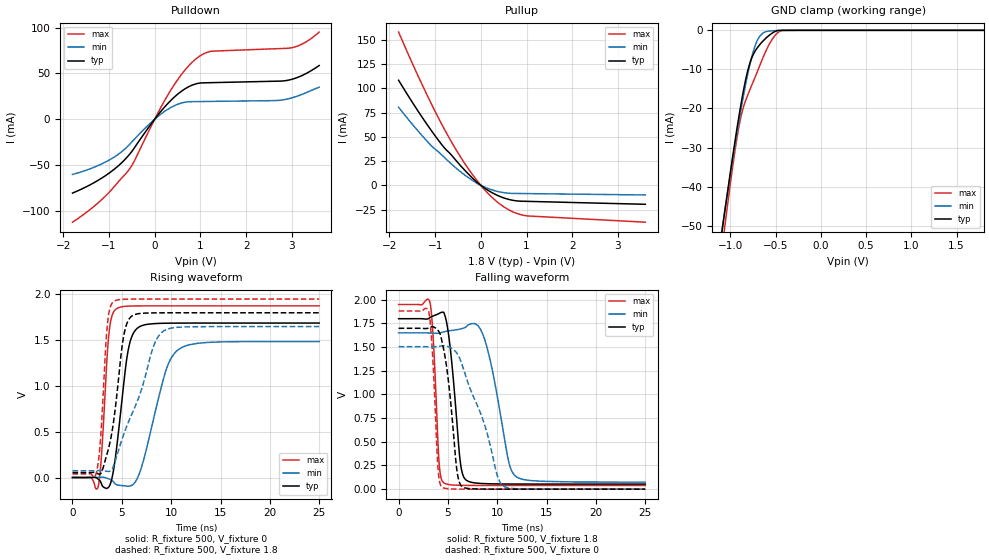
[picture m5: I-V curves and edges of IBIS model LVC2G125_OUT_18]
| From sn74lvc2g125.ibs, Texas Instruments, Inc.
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[Model]   LVC2G125_OUT_18
Model_type  3-state
Enable   Active-Low
Vref =   0
Rref =   1k
Cref =   30p
Vmeas =   0.9
| variable   typ   min   max
C_comp   6.12pF   5.33pF   6.95pF
| C_pullup   9.53pF   6.44pF   11.63pF
| C_pulldown   10.67pF   6.75pF   16.56pF
| C_tri-state   6.12pF   5.33pF   6.95pF
[Temperature Range]   40   100   -40
| Ambient temperature   25   85   -40
[Voltage range]   1.8   1.65   1.95
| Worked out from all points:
|   slope of the pulldown table from 0 to 0.27 V, typ, clamps not added: 16.6 ohm
|   slope of the pullup table from 0 to 0.27 V, typ, clamps not added: 33.1 ohm
|   GND clamp passes 1 mA (typ) near -0.56 V on its own axis
|   rising waveform, R_fixture 500, V_fixture 0: 20-80 % time 1.09ns typ, 2.07ns min, 612ps max; typ from 0 V to 1.69 V
|   falling waveform, R_fixture 500, V_fixture 1.8: 20-80 % time 861ps typ, 1.63ns min, 501ps max; typ from 1.8 V to 0.054 V
|   rising waveform, R_fixture 500, V_fixture 1.8: 20-80 % time 1.21ns typ, 2.99ns min, 614ps max; typ from 0.054 V to 1.8 V
|   falling waveform, R_fixture 500, V_fixture 0: 20-80 % time 993ps typ, 2.86ns min, 513ps max; typ from 1.7 V to 0 V
[GND Clamp]
| LVC2G125_OUT_18
|   Voltage   I(typ)   I(min)   I(max)
-1.8V     -180mA     -170.1mA   -199.3mA
-1.09V    -50.88mA   -50.33mA   -55.25mA
-1.055V   -45.05mA   -44.93mA   -48.78mA
-920mV    -23.93mA   -25.16mA   -26.38mA
-875mV    -17.74mA   -19.13mA   -21.2mA
-820mV    -11.37mA   -12.41mA   -17.19mA
-775mV    -7.672mA   -7.72mA    -14.61mA
-725mV    -5.204mA   -3.781mA   -11.81mA
-630mV    -2.493mA   -554.4uA   -6.414mA
-530mV    -582.7uA   -113.1uA   -1.993mA
-430mV    -5.996uA   -38.12uA   -30.78uA
1.8V      20.22pA    26.25nA    581.3pA
[Pulldown]
| LVC2G125_OUT_18
|   Voltage   I(typ)   I(min)   I(max)
-1.8V     -80.79mA   -60.4mA    -112.6mA
-1.07V    -61.45mA   -46.66mA   -83.63mA
-570mV    -39.5mA    -28.49mA   -55.7mA
-445mV    -31.3mA    -21.92mA   -45.66mA
-80mV     -5.366mA   -3.62mA    -8.004mA
270mV     16.26mA    10.32mA    24.98mA
615mV     31.62mA    18.09mA    50.79mA
930mV     39mA       19.26mA    67.03mA
1.25V     39.98mA    19.47mA    74.33mA
2.865V    42.16mA    21.66mA    77.49mA
3.215V    47.55mA    26.98mA    81.88mA
3.6V      58.7mA     34.88mA    95.26mA
[Pullup]
| LVC2G125_OUT_18
|   Voltage   I(typ)   I(min)   I(max)
-1.8V     108.2mA    80.38mA    157.8mA
-1.425V   80.1mA     58.76mA    117.9mA
-1.08V    56.19mA    40.61mA    83.64mA
-815mV    39.58mA    29.51mA    59.35mA
-595mV    28.49mA    19.95mA    40.88mA
-320mV    14.01mA    9.554mA    20.26mA
-45mV     1.662mA    1.097mA    2.622mA
175mV     -5.605mA   -3.539mA   -9.138mA
400mV     -11.07mA   -6.643mA   -18.6mA
700mV     -15.37mA   -8.29mA    -27.23mA
1V        -16.44mA   -8.458mA   -31.32mA
3.6V      -19.49mA   -9.866mA   -37.91mA
[Ramp]
| LVC2G125_OUT_18
| variable   typ   min   max
dV/dt_r   1.08/1.17E-09   0.95/2.19E-09   1.20/6.56E-10
dV/dt_f   1.09/9.11E-10   1.01/1.77E-09   1.18/5.26E-10
R_load = 500
[Rising Waveform]
| LVC2G125_OUT_18
R_fixture =   500
C_fixture =   0
L_fixture =   0
V_fixture =   0
V_fixture_min = 0
V_fixture_max = 0
|   Time   V(typ)   V(min)   V(max)
0s        111.1pV    7.498nV    2.783nV
2.605ns   -18.45mV   2.033mV    -98.12mV
2.93ns    -67.64mV   3.18mV     227.3mV
3.69ns    -102.2mV   -15.42mV   1.566V
4.46ns    313.2mV    -78.72mV   1.845V
5.625ns   1.38V      -95.92mV   1.873V
6.72ns    1.643V     27.63mV    1.875V
9.45ns    1.686V     1.163V     1.876V
10.74ns   1.687V     1.398V     1.876V
24.99ns   1.688V     1.486V     1.876V
[Falling Waveform]
| LVC2G125_OUT_18
R_fixture =   500
C_fixture =   0
L_fixture =   0
V_fixture =   1.8
V_fixture_min = 1.65
V_fixture_max = 1.95
|   Time   V(typ)   V(min)   V(max)
0s        1.8V       1.65V      1.95V
3.165ns   1.81V      1.648V     1.977V
4.105ns   1.856V     1.648V     277.4mV
4.575ns   1.866V     1.661V     66.96mV
5.25ns    1.473V     1.674V     46.54mV
6.265ns   276.3mV    1.692V     40.61mV
6.82ns    97.43mV    1.712V     39.72mV
8.71ns    58.67mV    1.584V     38.94mV
11.83ns   54.11mV    138.8mV    38.84mV
24.99ns   53.62mV    74.04mV    38.83mV
[Rising Waveform]
| LVC2G125_OUT_18
R_fixture =   500
C_fixture =   0
L_fixture =   0
V_fixture =   1.8
V_fixture_min = 1.65
V_fixture_max = 1.95
|   Time   V(typ)   V(min)   V(max)
0s        53.59mV    73.89mV    38.81mV
2.45ns    49.19mV    74.54mV    67.9mV
2.835ns   39.85mV    76.42mV    414.2mV
3.535ns   271.2mV    66.66mV    1.668V
4.19ns    632.1mV    138.6mV    1.925V
5.04ns    1.445V     424.9mV    1.947V
5.6ns     1.706V     588.9mV    1.949V
8.25ns    1.799V     1.445V     1.95V
9.225ns   1.8V       1.6V       1.95V
24.99ns   1.8V       1.65V      1.95V
[Falling Waveform]
| LVC2G125_OUT_18
R_fixture =   500
C_fixture =   0
L_fixture =   0
V_fixture =   0
V_fixture_min = 0
V_fixture_max = 0
|   Time   V(typ)   V(min)   V(max)
0s        1.699V     1.505V     1.882V
3.055ns   1.703V     1.503V     1.871V
3.43ns    1.714V     1.503V     1.436V
3.99ns    1.677V     1.506V     222.9mV
4.41ns    1.553V     1.514V     20.07mV
5.06ns    1.131V     1.504V     4.437mV
5.915ns   192.5mV    1.435V     1.005mV
6.44ns    26.55mV    1.31V      479.3uV
10.64ns   227.5uV    32.23mV    26.62uV
24.99ns   23.52uV    47.62uV    15.81uV
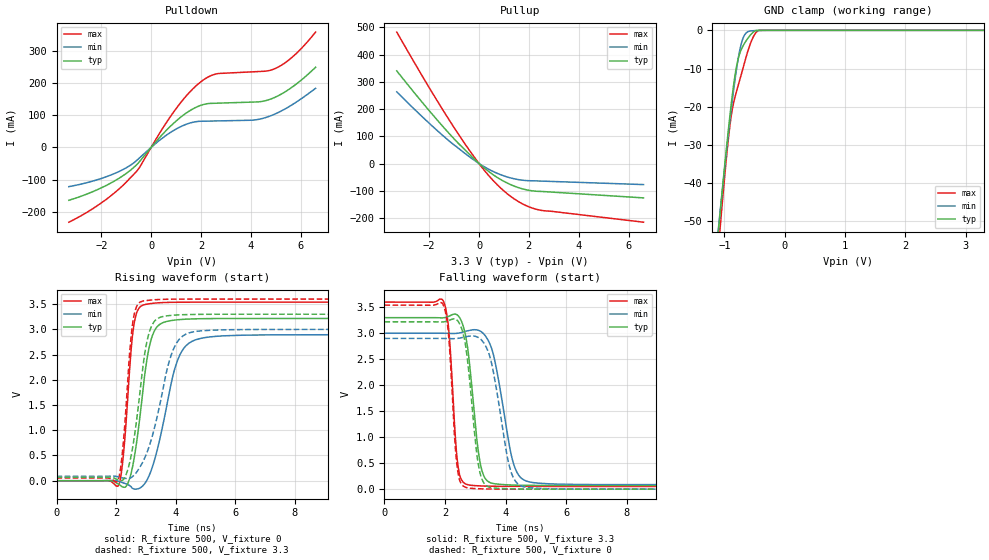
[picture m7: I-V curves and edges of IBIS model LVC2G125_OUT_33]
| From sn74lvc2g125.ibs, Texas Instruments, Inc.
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[Model]   LVC2G125_OUT_33
Model_type  3-state
Enable   Active-Low
Vref =   0
Rref =   500
Cref =   50p
Vmeas =   1.5
| variable   typ   min   max
C_comp   5.79pF   4.93pF   6.96pF
| C_pullup   10.69pF   5.83pF   13.59pF
| C_pulldown   9.27pF   6.33pF   12.94pF
| C_tri-state   5.79pF   4.93pF   6.96pF
[Temperature Range]   40   100   -40
| Ambient temperature   25   85   -40
[Voltage range]   3.3   3   3.6
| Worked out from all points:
|   slope of the pulldown table from 0 to 0.495 V, typ, clamps not added: 11.3 ohm
|   slope of the pullup table from 0 to 0.495 V, typ, clamps not added: 13.6 ohm
|   GND clamp passes 1 mA (typ) near -0.56 V on its own axis
|   rising waveform, R_fixture 500, V_fixture 0: 20-80 % time 427ps typ, 654ps min, 267ps max; typ from 0 V to 3.22 V
|   falling waveform, R_fixture 500, V_fixture 3.3: 20-80 % time 342ps typ, 520ps min, 223ps max; typ from 3.3 V to 0.069 V
|   rising waveform, R_fixture 500, V_fixture 3.3: 20-80 % time 430ps typ, 707ps min, 266ps max; typ from 0.069 V to 3.3 V
|   falling waveform, R_fixture 500, V_fixture 0: 20-80 % time 335ps typ, 497ps min, 219ps max; typ from 3.22 V to 0 V
[GND Clamp]
| LVC2G125_OUT_33
|   Voltage   I(typ)   I(min)   I(max)
-3.3V     -473.8mA   -443.8mA   -525.9mA
-1.095V   -51.73mA   -51.11mA   -56.19mA
-1.075V   -48.37mA   -48mA      -52.46mA
-1.055V   -45.05mA   -44.93mA   -48.78mA
-970mV    -31.42mA   -32.24mA   -33.94mA
-900mV    -21.09mA   -22.43mA   -23.84mA
-820mV    -11.37mA   -12.41mA   -17.19mA
-715mV    -4.844mA   -3.19mA    -11.24mA
-610mV    -2.043mA   -350uA     -5.373mA
-505mV    -273.4uA   -88.32uA   -1.237mA
-420mV    -4.422uA   -33.13uA   -10.75uA
3.3V      25.08pA    99.5nA     647.2pA
[Pulldown]
| LVC2G125_OUT_33
|   Voltage   I(typ)   I(min)   I(max)
-3.3V     -163.8mA   -121.5mA   -231.7mA
-1.815V   -118.4mA   -91.27mA   -161.8mA
-625mV    -56.81mA   -43.38mA   -77.79mA
280mV     25.42mA    18.41mA    36.51mA
915mV     75.81mA    53.13mA    111.1mA
1.48V     110.3mA    73.79mA    165.8mA
2V        130.7mA    81.21mA    203.8mA
2.65V     137.3mA    82.24mA    228.6mA
4.165V    140.9mA    85.35mA    234.8mA
4.975V    155.6mA    103.8mA    244.6mA
5.73V     191mA      135.9mA    284.5mA
6.6V      248.7mA    183.2mA    357.7mA
[Pullup]
| LVC2G125_OUT_33
|   Voltage   I(typ)   I(min)   I(max)
-3.3V     340.1mA    263.1mA    482.7mA
-1.755V   168mA      127.5mA    241.8mA
-1.04V    94.5mA     70.94mA    137.4mA
-545mV    48.46mA    35.8mA     69.49mA
5mV       -411.6uA   -298.4uA   -611.3uA
375mV     -28.41mA   -20.31mA   -42.79mA
795mV     -54.75mA   -38.41mA   -83.6mA
1.21V     -75.13mA   -51.47mA   -116.5mA
1.825V    -94.95mA   -62.02mA   -151.9mA
2.435V    -102.4mA   -64.33mA   -170.9mA
6.6V      -126.2mA   -77.39mA   -215.5mA
[Ramp]
| LVC2G125_OUT_33
| variable   typ   min   max
dV/dt_r   2.01/4.51E-10   1.84/6.99E-10   2.19/2.78E-10
dV/dt_f   1.98/3.57E-10   1.79/5.38E-10   2.16/2.34E-10
R_load = 500
[Rising Waveform]
| LVC2G125_OUT_33
R_fixture =   500
C_fixture =   0
L_fixture =   0
V_fixture =   0
V_fixture_min = 0
V_fixture_max = 0
|   Time   V(typ)   V(min)   V(max)
0s        141.8pV    4.978nV    2.399nV
2.08ns    -67.26mV   -10.35mV   -93.74mV
2.245ns   -128.6mV   -44.03mV   512.7mV
2.5ns     139.4mV    -116.6mV   2.568V
2.59ns    392.8mV    -161.2mV   3.058V
2.985ns   2.204V     -36.82mV   3.494V
3.32ns    3.005V     474mV      3.521V
4.065ns   3.19V      2.389V     3.537V
4.835ns   3.21V      2.82V      3.538V
24.99ns   3.216V     2.894V     3.539V
[Falling Waveform]
| LVC2G125_OUT_33
R_fixture =   500
C_fixture =   0
L_fixture =   0
V_fixture =   3.3
V_fixture_min = 3
V_fixture_max = 3.6
|   Time   V(typ)   V(min)   V(max)
0s        3.3V       3V         3.6V
1.95ns    3.298V     3V         3.613V
2.125ns   3.326V     2.997V     3.056V
2.425ns   3.342V     3.001V     465.2mV
2.775ns   2.59V      3.051V     82.82mV
3.29ns    243.5mV    2.979V     60.1mV
3.62ns    106.1mV    2.533V     56.23mV
4.265ns   78.67mV    483.6mV    53.97mV
4.785ns   72.9mV     139.4mV    53.52mV
24.99ns   69.39mV    85.93mV    53.23mV
[Rising Waveform]
| LVC2G125_OUT_33
R_fixture =   500
C_fixture =   0
L_fixture =   0
V_fixture =   3.3
V_fixture_min = 3
V_fixture_max = 3.6
|   Time   V(typ)   V(min)   V(max)
0s        69.35mV    85.87mV    53.2mV
2.065ns   19.5mV     78.71mV    9.697mV
2.23ns    14.03mV    52.8mV     674.3mV
2.55ns    641.9mV    82.2mV     3.095V
2.9ns     2.255V     376.3mV    3.561V
3.085ns   2.882V     638.6mV    3.576V
3.31ns    3.175V     1.099V     3.587V
3.905ns   3.279V     2.579V     3.598V
4.58ns    3.295V     2.949V     3.6V
24.99ns   3.3V       3V         3.6V
[Falling Waveform]
| LVC2G125_OUT_33
R_fixture =   500
C_fixture =   0
L_fixture =   0
V_fixture =   0
V_fixture_min = 0
V_fixture_max = 0
|   Time   V(typ)   V(min)   V(max)
0s        3.22V      2.9V       3.542V
1.94ns    3.218V     2.9V       3.548V
2.115ns   3.243V     2.898V     2.98V
2.405ns   3.248V     2.901V     410.4mV
2.715ns   2.611V     2.937V     28.68mV
3.22ns    189.4mV    2.859V     5.999mV
3.55ns    28.14mV    2.387V     2.556mV
4.155ns   6.911mV    378.5mV    680.8uV
4.62ns    2.618mV    42.49mV    304.9uV
24.99ns   40.08uV    51.12uV    31.83uV
